VERSION 5.8 ;
BUSBITCHARS "[]" ;
DIVIDERCHAR "/" ;
UNITS
    DATABASE MICRONS 1000 ;
END UNITS

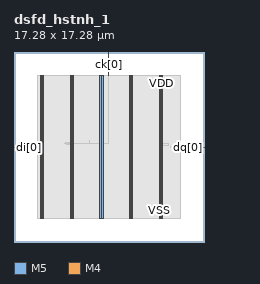
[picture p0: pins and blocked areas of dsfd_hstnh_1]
MACRO dsfd_hstnh_1
  FOREIGN dsfd_hstnh_1 0 0 ;
  CLASS BLOCK ;
  SIZE 17.28 BY 17.28 ;
  PIN ck[0]
    DIRECTION INPUT ;
    USE SIGNAL ;
    PORT
      LAYER M5 ;
        RECT  8.592 17.196 8.616 17.28 ;
    END
    PORT
      LAYER M5 ;
        RECT  8.592 15.143 8.616 17.232 ;
    END
  END ck[0]
  PIN di[0]
    DIRECTION INPUT ;
    USE SIGNAL ;
    PORT
      LAYER M4 ;
        RECT  0 8.592 0.084 8.616 ;
    END
    PORT
      LAYER M4 ;
        RECT  0.06 8.592 2.408 8.616 ;
    END
  END di[0]
  PIN dq[0]
    DIRECTION OUTPUT ;
    USE SIGNAL ;
    PORT
      LAYER M4 ;
        RECT  17.196 8.592 17.28 8.616 ;
    END
    PORT
      LAYER M4 ;
        RECT  17.161 8.592 17.244 8.616 ;
    END
  END dq[0]
  PIN VDD
    DIRECTION INOUT ;
    USE POWER ;
    PORT
      LAYER M5 ;
        RECT  13.392 2.151 13.512 15.129 ;
        RECT  10.692 2.151 10.812 15.129 ;
        RECT  7.992 2.151 8.112 15.129 ;
        RECT  5.292 2.151 5.412 15.129 ;
        RECT  2.592 2.151 2.712 15.129 ;
    END
  END VDD
  PIN VSS
    DIRECTION INOUT ;
    USE GROUND ;
    PORT
      LAYER M5 ;
        RECT  13.2 2.137 13.32 15.143 ;
        RECT  10.5 2.137 10.62 15.143 ;
        RECT  7.8 2.137 7.92 15.143 ;
        RECT  5.1 2.137 5.22 15.143 ;
        RECT  2.4 2.137 2.52 15.143 ;
    END
  END VSS
  # OT_OBS_CLOSED layer=M5 d_um=1.536 added=0
  OBS
    LAYER RVTN ;
     RECT  2.16 2.16 15.12 2.295 ;
     RECT  2.16 2.565 15.12 2.835 ;
     RECT  2.16 3.105 15.12 3.375 ;
     RECT  2.16 3.645 15.12 3.915 ;
     RECT  2.16 4.185 15.12 4.455 ;
     RECT  2.16 4.725 15.12 4.995 ;
     RECT  2.16 5.265 15.12 5.535 ;
     RECT  2.16 5.805 15.12 6.075 ;
     RECT  2.16 6.345 15.12 6.615 ;
     RECT  2.16 6.885 15.12 7.155 ;
     RECT  2.16 7.425 15.12 7.695 ;
     RECT  2.16 7.965 15.12 8.235 ;
     RECT  2.16 8.505 15.12 8.775 ;
     RECT  2.16 9.045 15.12 9.315 ;
     RECT  2.16 9.585 15.12 9.855 ;
     RECT  2.16 10.125 15.12 10.395 ;
     RECT  2.16 10.665 15.12 10.935 ;
     RECT  2.16 11.205 15.12 11.475 ;
     RECT  2.16 11.745 15.12 12.015 ;
     RECT  2.16 12.285 15.12 12.555 ;
     RECT  2.16 12.825 15.12 13.095 ;
     RECT  2.16 13.365 15.12 13.635 ;
     RECT  2.16 13.905 15.12 14.175 ;
     RECT  2.16 14.445 15.12 14.715 ;
     RECT  2.16 14.985 15.12 15.12 ;
    LAYER RVTP ;
     RECT  2.16 2.295 15.12 2.565 ;
     RECT  2.16 2.835 15.12 3.105 ;
     RECT  2.16 3.375 15.12 3.645 ;
     RECT  2.16 3.915 15.12 4.185 ;
     RECT  2.16 4.455 15.12 4.725 ;
     RECT  2.16 4.995 15.12 5.265 ;
     RECT  2.16 5.535 15.12 5.805 ;
     RECT  2.16 6.075 15.12 6.345 ;
     RECT  2.16 6.615 15.12 6.885 ;
     RECT  2.16 7.155 15.12 7.425 ;
     RECT  2.16 7.695 15.12 7.965 ;
     RECT  2.16 8.235 15.12 8.505 ;
     RECT  2.16 8.775 15.12 9.045 ;
     RECT  2.16 9.315 15.12 9.585 ;
     RECT  2.16 9.855 15.12 10.125 ;
     RECT  2.16 10.395 15.12 10.665 ;
     RECT  2.16 10.935 15.12 11.205 ;
     RECT  2.16 11.475 15.12 11.745 ;
     RECT  2.16 12.015 15.12 12.285 ;
     RECT  2.16 12.555 15.12 12.825 ;
     RECT  2.16 13.095 15.12 13.365 ;
     RECT  2.16 13.635 15.12 13.905 ;
     RECT  2.16 14.175 15.12 14.445 ;
     RECT  2.16 14.715 15.12 14.985 ;
    LAYER M1 ;
     RECT  2.16 2.151 15.12 15.129 ;
    LAYER M2 ;
     RECT  2.16 2.151 15.12 15.129 ;
     RECT  15.12 8.514 17.195 8.532 ;
    LAYER M3 ;
     RECT  2.415 2.143 2.505 2.413 ;
     RECT  5.115 2.143 5.205 2.413 ;
     RECT  7.815 2.143 7.905 2.413 ;
     RECT  10.515 2.143 10.605 2.413 ;
     RECT  13.215 2.143 13.305 2.413 ;
     RECT  14.76 8.401 14.778 8.501 ;
     RECT  2.415 2.413 2.697 8.587 ;
     RECT  17.172 8.509 17.19 8.621 ;
     RECT  14.256 8.581 14.274 8.699 ;
     RECT  2.304 8.587 2.697 8.735 ;
     RECT  13.215 2.413 13.497 8.815 ;
     RECT  5.115 2.413 5.397 8.851 ;
     RECT  4.788 8.851 5.397 8.941 ;
     RECT  13.215 8.815 14.094 8.969 ;
     RECT  7.815 2.413 8.097 8.977 ;
     RECT  4.644 8.941 5.397 9.005 ;
     RECT  7.815 8.977 8.442 9.149 ;
     RECT  6.876 9.085 6.894 9.275 ;
     RECT  2.415 8.735 2.697 14.867 ;
     RECT  5.115 9.005 5.397 14.867 ;
     RECT  7.815 9.149 8.097 14.867 ;
     RECT  10.515 2.413 10.797 14.867 ;
     RECT  13.215 8.969 13.497 14.867 ;
     RECT  2.415 14.867 2.505 15.137 ;
     RECT  5.115 14.867 5.205 15.137 ;
     RECT  7.815 14.867 7.905 15.137 ;
     RECT  10.515 14.867 10.605 15.137 ;
     RECT  13.215 14.867 13.305 15.137 ;
    LAYER M4 ;
     RECT  2.408 2.148 2.512 15.132 ;
     RECT  2.512 2.418 2.704 14.862 ;
     RECT  4.633 8.976 5.108 9 ;
     RECT  5.108 2.148 5.212 15.132 ;
     RECT  5.212 2.418 5.404 14.862 ;
     RECT  5.404 8.976 7.808 9 ;
     RECT  7.808 2.148 7.912 15.132 ;
     RECT  7.912 2.418 8.104 14.862 ;
     RECT  8.104 8.976 8.627 9 ;
     RECT  10.508 2.148 10.612 15.132 ;
     RECT  10.612 2.418 10.804 14.862 ;
     RECT  13.208 2.148 13.312 15.132 ;
     RECT  13.312 2.418 13.504 14.862 ;
    LAYER M5 ;
     RECT  2.4 2.137 2.52 2.151 ;
     RECT  5.1 2.137 5.22 2.151 ;
     RECT  7.8 2.137 7.92 2.151 ;
     RECT  10.5 2.137 10.62 2.151 ;
     RECT  13.2 2.137 13.32 2.151 ;
     RECT  7.8 2.151 8.112 8.965 ;
     RECT  2.4 2.151 2.712 15.129 ;
     RECT  5.1 2.151 5.412 15.129 ;
     RECT  10.5 2.151 10.812 15.129 ;
     RECT  13.2 2.151 13.512 15.129 ;
     RECT  2.4 15.129 2.52 15.143 ;
     RECT  5.1 15.129 5.22 15.143 ;
     RECT  7.8 8.965 8.616 15.143 ;
     RECT  10.5 15.129 10.62 15.143 ;
     RECT  13.2 15.129 13.32 15.143 ;
  END
END dsfd_hstnh_1
END LIBRARY
